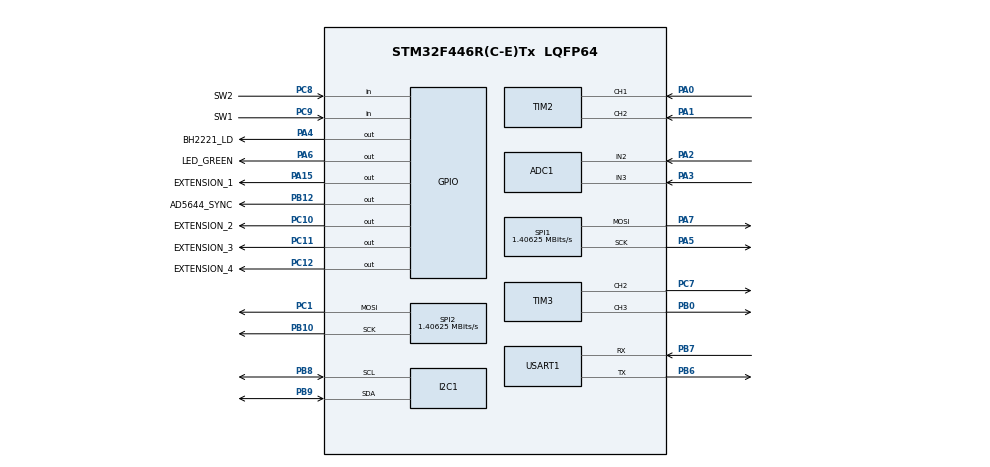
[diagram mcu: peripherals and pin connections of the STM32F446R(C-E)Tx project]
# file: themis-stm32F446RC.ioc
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ADC1.Channel-3\#ChannelRegularConversion=ADC_CHANNEL_2
ADC1.NbrOfConversionFlag=1
ADC1.Rank-3\#ChannelRegularConversion=1
ADC1.SamplingTime-3\#ChannelRegularConversion=ADC_SAMPLETIME_3CYCLES
ADC1.master=1
Dma.Request0=SPI1_TX
Dma.Request1=SPI2_TX
Dma.Request2=USART1_TX
Dma.SPI1_TX.0.Direction=DMA_MEMORY_TO_PERIPH
Dma.SPI1_TX.0.FIFOMode=DMA_FIFOMODE_DISABLE
Dma.SPI1_TX.0.Instance=DMA2_Stream3
Dma.SPI1_TX.0.MemDataAlignment=DMA_MDATAALIGN_BYTE
Dma.SPI1_TX.0.MemInc=DMA_MINC_ENABLE
Dma.SPI1_TX.0.Mode=DMA_NORMAL
Dma.SPI1_TX.0.PeriphDataAlignment=DMA_PDATAALIGN_BYTE
Dma.SPI1_TX.0.PeriphInc=DMA_PINC_DISABLE
Dma.SPI1_TX.0.Priority=DMA_PRIORITY_LOW
Dma.SPI2_TX.1.Direction=DMA_MEMORY_TO_PERIPH
Dma.SPI2_TX.1.FIFOMode=DMA_FIFOMODE_DISABLE
Dma.SPI2_TX.1.Instance=DMA1_Stream4
Dma.SPI2_TX.1.MemDataAlignment=DMA_MDATAALIGN_BYTE
Dma.SPI2_TX.1.MemInc=DMA_MINC_ENABLE
Dma.SPI2_TX.1.Mode=DMA_NORMAL
Dma.SPI2_TX.1.PeriphDataAlignment=DMA_PDATAALIGN_BYTE
Dma.SPI2_TX.1.PeriphInc=DMA_PINC_DISABLE
Dma.SPI2_TX.1.Priority=DMA_PRIORITY_LOW
Dma.USART1_TX.2.Direction=DMA_MEMORY_TO_PERIPH
Dma.USART1_TX.2.FIFOMode=DMA_FIFOMODE_DISABLE
Dma.USART1_TX.2.Instance=DMA2_Stream7
Dma.USART1_TX.2.MemDataAlignment=DMA_MDATAALIGN_BYTE
Dma.USART1_TX.2.MemInc=DMA_MINC_ENABLE
Dma.USART1_TX.2.Mode=DMA_NORMAL
Dma.USART1_TX.2.PeriphDataAlignment=DMA_PDATAALIGN_BYTE
Dma.USART1_TX.2.PeriphInc=DMA_PINC_DISABLE
Dma.USART1_TX.2.Priority=DMA_PRIORITY_LOW
Mcu.Family=STM32F4
Mcu.Name=STM32F446R(C-E)Tx
Mcu.Package=LQFP64
NVIC.DMA1_Stream4_IRQn=true\:0\:0\:false\:false\:true\:false\:true
NVIC.DMA2_Stream3_IRQn=true\:0\:0\:false\:false\:true\:false\:true
NVIC.DMA2_Stream7_IRQn=true\:0\:0\:false\:false\:true\:false\:true
NVIC.PriorityGroup=NVIC_PRIORITYGROUP_4
NVIC.TIM1_UP_TIM10_IRQn=true\:0\:0\:false\:false\:true\:true\:true
NVIC.TIM2_IRQn=true\:0\:0\:false\:false\:true\:true\:true
NVIC.USART1_IRQn=true\:0\:0\:false\:false\:true\:true\:true
PA0-WKUP.Signal=S_TIM2_CH1_ETR
PA1.Signal=S_TIM2_CH2
PA13.Mode=Serial_Wire
PA13.Signal=SYS_JTMS-SWDIO
PA14.Mode=Serial_Wire
PA14.Signal=SYS_JTCK-SWCLK
PA15.GPIO_Label=EXTENSION_1
PA15.Signal=GPIO_Output
PA2.Signal=ADCx_IN2
PA3.Signal=ADCx_IN3
PA4.GPIO_Label=BH2221_LD
PA4.GPIO_Speed=GPIO_SPEED_FREQ_HIGH
PA4.PinState=GPIO_PIN_SET
PA4.Signal=GPIO_Output
PA5.Mode=TX_Only_Simplex_Unidirect_Master
PA5.Signal=SPI1_SCK
PA6.GPIO_Label=LED_GREEN
PA6.Signal=GPIO_Output
PA7.Mode=TX_Only_Simplex_Unidirect_Master
PA7.Signal=SPI1_MOSI
PB0.Signal=S_TIM3_CH3
PB10.Mode=TX_Only_Simplex_Unidirect_Master
PB10.Signal=SPI2_SCK
PB12.GPIO_Label=AD5644_SYNC
PB12.GPIO_Speed=GPIO_SPEED_FREQ_HIGH
PB12.PinState=GPIO_PIN_SET
PB12.Signal=GPIO_Output
PB6.Mode=Asynchronous
PB6.Signal=USART1_TX
PB7.Mode=Asynchronous
PB7.Signal=USART1_RX
PB8.Mode=I2C
PB8.Signal=I2C1_SCL
PB9.Mode=I2C
PB9.Signal=I2C1_SDA
PC1.Mode=TX_Only_Simplex_Unidirect_Master
PC1.Signal=SPI2_MOSI
PC10.GPIO_Label=EXTENSION_2
PC10.Signal=GPIO_Output
PC11.GPIO_Label=EXTENSION_3
PC11.Signal=GPIO_Output
PC12.GPIO_Label=EXTENSION_4
PC12.Signal=GPIO_Output
PC7.Signal=S_TIM3_CH2
PC8.GPIO_Label=SW2
PC8.Signal=GPIO_Input
PC9.GPIO_Label=SW1
PC9.Signal=GPIO_Input
PH0-OSC_IN.Mode=HSE-External-Oscillator
PH0-OSC_IN.Signal=RCC_OSC_IN
PH1-OSC_OUT.Mode=HSE-External-Oscillator
PH1-OSC_OUT.Signal=RCC_OSC_OUT
ProjectManager.HeapSize=0x200
ProjectManager.StackSize=0x400
ProjectManager.TargetToolchain=STM32CubeIDE
RCC.AHBFreq_Value=180000000
RCC.APB1CLKDivider=RCC_HCLK_DIV4
RCC.APB1Freq_Value=45000000
RCC.APB1TimFreq_Value=90000000
RCC.APB2CLKDivider=RCC_HCLK_DIV4
RCC.APB2Freq_Value=45000000
RCC.APB2TimFreq_Value=90000000
RCC.CortexFreq_Value=180000000
RCC.HCLKFreq_Value=180000000
RCC.HSE_VALUE=16000000
RCC.PLLM=8
RCC.PLLN=180
RCC.PLLQ=5
RCC.PLLSourceVirtual=RCC_PLLSOURCE_HSE
RCC.SYSCLKFreq_VALUE=180000000
RCC.SYSCLKSource=RCC_SYSCLKSOURCE_PLLCLK
RCC.USBFreq_Value=72000000
RCC.VCOOutputFreq_Value=360000000
SH.ADCx_IN2.0=ADC1_IN2,IN2
SH.ADCx_IN3.0=ADC1_IN3,IN3
SH.S_TIM2_CH1_ETR.0=TIM2_CH1,Input_Capture1_from_TI1
SH.S_TIM2_CH2.0=TIM2_CH2,Input_Capture2_from_TI2
SH.S_TIM3_CH2.0=TIM3_CH2,PWM Generation2 CH2
SH.S_TIM3_CH3.0=TIM3_CH3,PWM Generation3 CH3
SPI1.BaudRatePrescaler=SPI_BAUDRATEPRESCALER_32
SPI1.CLKPhase=SPI_PHASE_2EDGE
SPI1.CLKPolarity=SPI_POLARITY_HIGH
SPI1.CalculateBaudRate=1.40625 MBits/s
SPI1.DataSize=SPI_DATASIZE_8BIT
SPI1.Direction=SPI_DIRECTION_2LINES
SPI1.Mode=SPI_MODE_MASTER
SPI1.VirtualType=VM_MASTER
SPI2.BaudRatePrescaler=SPI_BAUDRATEPRESCALER_32
SPI2.CLKPolarity=SPI_POLARITY_HIGH
SPI2.CalculateBaudRate=1.40625 MBits/s
SPI2.Direction=SPI_DIRECTION_2LINES
SPI2.Mode=SPI_MODE_MASTER
SPI2.VirtualType=VM_MASTER
TIM2.Channel-Input_Capture1_from_TI1=TIM_CHANNEL_1
TIM2.Channel-Input_Capture2_from_TI2=TIM_CHANNEL_2
TIM3.Channel-PWM\ Generation2\ CH2=TIM_CHANNEL_2
TIM3.Channel-PWM\ Generation3\ CH3=TIM_CHANNEL_3
USART1.VirtualMode=VM_ASYNC
VP_TIM1_VS_ClockSourceINT.Mode=Internal
VP_TIM2_VS_ClockSourceINT.Mode=Internal
VP_TIM3_VS_ClockSourceINT.Mode=Internal
board=custom

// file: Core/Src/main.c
/* USER CODE BEGIN Header */
/**
  ******************************************************************************
  * @file           : main.c
  * @brief          : Main program body
  ******************************************************************************
  * @attention
  *
  * <h2><center>&copy; Copyright (c) 2020 STMicroelectronics.
  * All rights reserved.</center></h2>
  *
  * This software component is licensed by ST under BSD 3-Clause license,
  * the "License"; You may not use this file except in compliance with the
  * License. You may obtain a copy of the License at:
  *                        opensource.org/licenses/BSD-3-Clause
  *
  ******************************************************************************
  */
/* USER CODE END Header */
#include "main.h"
#include "adc.h"
#include "i2c.h"
#include "spi.h"
#include "tim.h"
#include "usart.h"
#include "gpio.h"

void SystemClock_Config(void);

int main(void)
{

  /* MCU Configuration--------------------------------------------------------*/

  /* Reset of all peripherals, Initializes the Flash interface and the Systick. */
  HAL_Init();

  /* Configure the system clock */
  SystemClock_Config();

  /* Initialize all configured peripherals */
  MX_GPIO_Init();
  MX_I2C1_Init();
  MX_SPI1_Init();
  MX_SPI2_Init();
  MX_TIM1_Init();
  MX_TIM2_Init();
  MX_USART1_UART_Init();
  MX_ADC1_Init();
  MX_TIM3_Init();

  /* Infinite loop */
  while (1)
  {

    /* USER CODE BEGIN 3 */
	  HAL_GPIO_TogglePin(GPIOA, LED_GREEN_Pin);
	  HAL_Delay(200);

  }
  /* USER CODE END 3 */
}

void SystemClock_Config(void)
{
  RCC_OscInitTypeDef RCC_OscInitStruct = {0};
  RCC_ClkInitTypeDef RCC_ClkInitStruct = {0};

  /** Configure the main internal regulator output voltage
  */
  __HAL_RCC_PWR_CLK_ENABLE();
  __HAL_PWR_VOLTAGESCALING_CONFIG(PWR_REGULATOR_VOLTAGE_SCALE1);
  /** Initializes the RCC Oscillators according to the specified parameters
  * in the RCC_OscInitTypeDef structure.
  */
  RCC_OscInitStruct.OscillatorType = RCC_OSCILLATORTYPE_HSE;
  RCC_OscInitStruct.HSEState = RCC_HSE_ON;
  RCC_OscInitStruct.PLL.PLLState = RCC_PLL_ON;
  RCC_OscInitStruct.PLL.PLLSource = RCC_PLLSOURCE_HSE;
  RCC_OscInitStruct.PLL.PLLM = 8;
  RCC_OscInitStruct.PLL.PLLN = 180;
  RCC_OscInitStruct.PLL.PLLP = RCC_PLLP_DIV2;
  RCC_OscInitStruct.PLL.PLLQ = 5;
  RCC_OscInitStruct.PLL.PLLR = 2;
  if (HAL_RCC_OscConfig(&RCC_OscInitStruct) != HAL_OK)
  {
    Error_Handler();
  }
  /** Activate the Over-Drive mode
  */
  if (HAL_PWREx_EnableOverDrive() != HAL_OK)
  {
    Error_Handler();
  }
  /** Initializes the CPU, AHB and APB buses clocks
  */
  RCC_ClkInitStruct.ClockType = RCC_CLOCKTYPE_HCLK|RCC_CLOCKTYPE_SYSCLK
                              |RCC_CLOCKTYPE_PCLK1|RCC_CLOCKTYPE_PCLK2;
  RCC_ClkInitStruct.SYSCLKSource = RCC_SYSCLKSOURCE_PLLCLK;
  RCC_ClkInitStruct.AHBCLKDivider = RCC_SYSCLK_DIV1;
  RCC_ClkInitStruct.APB1CLKDivider = RCC_HCLK_DIV4;
  RCC_ClkInitStruct.APB2CLKDivider = RCC_HCLK_DIV2;

  if (HAL_RCC_ClockConfig(&RCC_ClkInitStruct, FLASH_LATENCY_5) != HAL_OK)
  {
    Error_Handler();
  }
}

void Error_Handler(void)
{
  /* USER CODE BEGIN Error_Handler_Debug */
  /* User can add his own implementation to report the HAL error return state */
	HAL_GPIO_TogglePin(GPIOA, LED_GREEN_Pin);
	HAL_Delay(50);
  /* USER CODE END Error_Handler_Debug */
}

/************************ (C) COPYRIGHT STMicroelectronics *****END OF FILE****/
